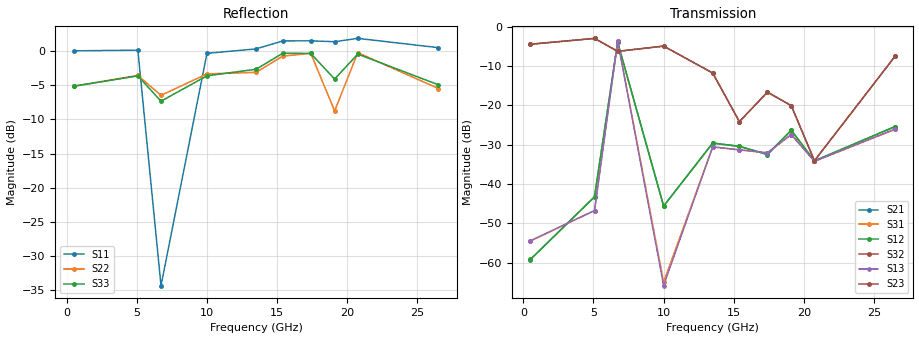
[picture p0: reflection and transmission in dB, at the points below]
! Mini-Circuits
! BBFCG2-672+
! Reference Information: Unit 10, Test Board, eCal w/ Auto Port Extension & Match Correction
! Temperature: -55 Degrees Celsius
# Hz S  dB  R 50
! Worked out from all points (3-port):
!   891 points, 500 MHz to 26.5 GHz, reference 50 ohm
!   strongest paths, dB at 500 MHz, 2.72 GHz, 6.6 GHz, 15.4 GHz, 26.5 GHz:
!     S32: -4.4, -9.0, -6.2, -24.1, -7.5
!     S31: -54.5, -35.2, -3.6, -31.3, -26.1
!     S21: -59.2, -48.4, -4.0, -30.4, -25.4
!   lowest |S11| = -34.3 dB at 6.725 GHz (marker M1), VSWR 1.04, Z = 50.3 + j1.9 ohm
!   |S11| at or under -10 dB: 6.144 GHz to 7.755 GHz (1.611 GHz wide, 23.2 % of centre); 18.2 GHz to 18.3 GHz (106.9 MHz wide, 0.586 % of centre)
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5e8  0.03 179.5  -59.21 -139.2  -54.44 110.6
     -59.23 -137.4  -5.15 -150.2  -4.41 -29.5
     -54.54 111.2  -4.41 -29.5  -5.14 -150.6
5.075e9  0.14 126.6  -43.24 39.4  -46.75 118.5
         -43.26 40.1  -3.57 146.1  -2.92 -133.7
         -46.74 118.4  -2.91 -133.8  -3.63 132.3
6.725e9  -34.34 78.6  -3.93 -155.4  -3.56 28.4
         -3.94 -155.2  -6.48 161.5  -6.22 165.9
         -3.56 28.4  -6.21 165.6  -7.34 170.1
1e10  -0.33 8.9  -45.61 -68.8  -65.88 62.5
      -45.60 -69.3  -3.34 71.6  -4.88 143.0
      -64.98 62.3  -4.88 142.7  -3.62 34.7
1.35e10  0.32 14.6  -29.56 -119.5  -30.53 -124.1
         -29.58 -119.2  -3.11 56.4  -11.74 -167.8
         -30.55 -124.1  -11.74 -168.1  -2.66 41.0
1.54e10  1.48 -82.4  -30.40 -152.1  -31.28 -154.9
         -30.43 -151.7  -0.74 -45.9  -24.12 125.9
         -31.32 -155.1  -24.11 125.2  -0.32 -56.3
1.74e10  1.50 6.4  -32.44 -130.3  -32.04 -128.4
         -32.48 -130.1  -0.33 53.9  -16.60 -174.5
         -32.07 -128.7  -16.60 -175.1  -0.35 48.0
1.91e10  1.37 -165.7  -26.31 175.7  -27.39 161.1
         -26.30 176.2  -8.75 -89.5  -20.04 93.2
         -27.40 161.3  -20.05 92.9  -4.10 -112.1
2.075e10  1.86 -92.3  -34.11 121.3  -34.20 111.9
          -34.10 121.9  -0.24 -53.1  -34.10 -145.1
          -34.21 112.0  -34.04 -145.2  -0.44 -62.7
2.65e10  0.50 146.6  -25.35 10.6  -26.03 13.6
         -25.39 11.3  -5.48 115.6  -7.44 -14.8
         -26.07 13.8  -7.48 -15.4  -4.94 105.9
